# Generated by OpenFakeRAM
VERSION 5.7 ;
BUSBITCHARS "[]" ;
PROPERTYDEFINITIONS
  MACRO width INTEGER ;
  MACRO depth INTEGER ;
  MACRO banks INTEGER ;
END PROPERTYDEFINITIONS
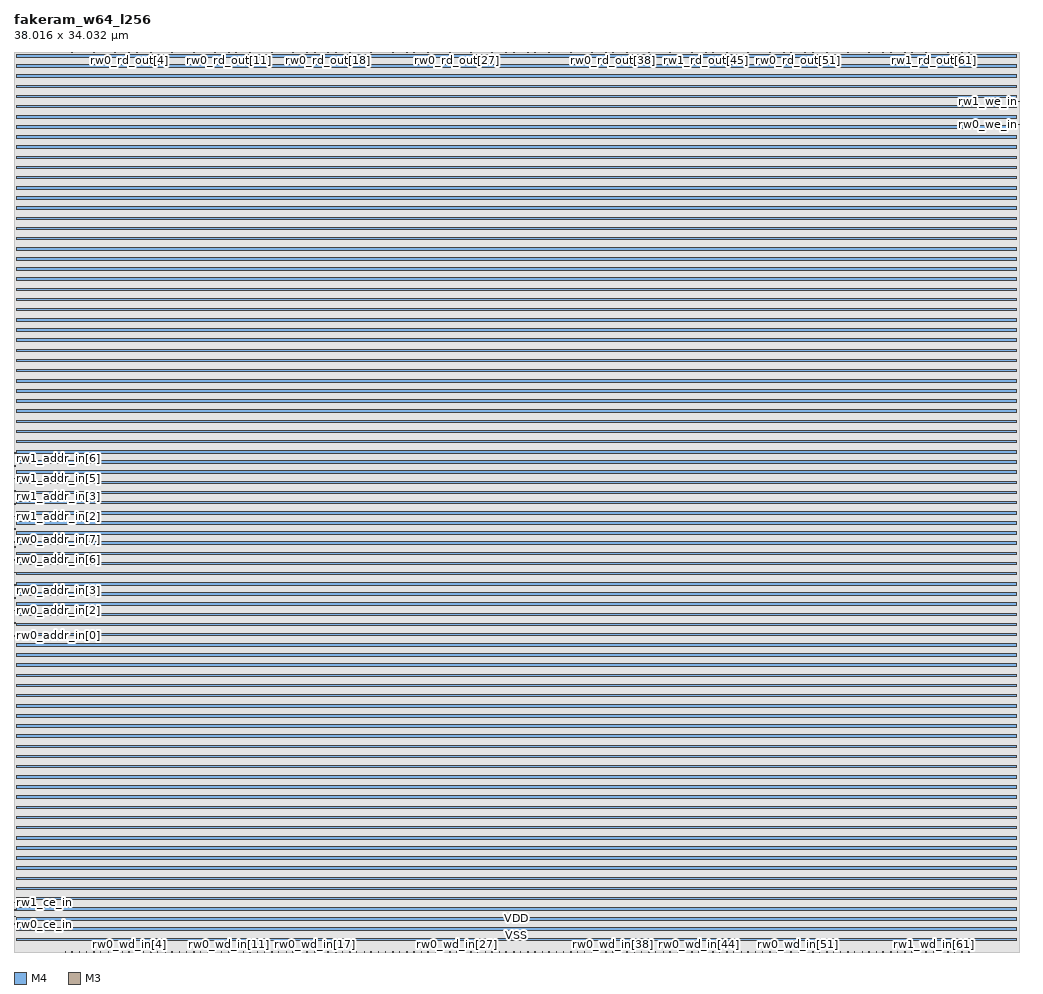
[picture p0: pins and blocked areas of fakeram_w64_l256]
MACRO fakeram_w64_l256
  PROPERTY width 64 ;
  PROPERTY depth 256 ;
  PROPERTY banks 1 ;
  FOREIGN fakeram_w64_l256 0 0 ;
  SYMMETRY X Y R90 ;
  SIZE 38.016 BY 34.032 ;
  CLASS BLOCK ;
  PIN rw0_clk
    DIRECTION INPUT ;
    USE SIGNAL ;
    SHAPE ABUTMENT ;
    PORT
      LAYER M4 ;
      RECT 0.000 1.044 0.048 1.068 ;
    END
  END rw0_clk
  PIN rw0_ce_in
    DIRECTION INPUT ;
    USE SIGNAL ;
    SHAPE ABUTMENT ;
    PORT
      LAYER M4 ;
      RECT 0.000 1.332 0.048 1.356 ;
    END
  END rw0_ce_in
  PIN rw1_clk
    DIRECTION INPUT ;
    USE SIGNAL ;
    SHAPE ABUTMENT ;
    PORT
      LAYER M4 ;
      RECT 0.000 1.572 0.048 1.596 ;
    END
  END rw1_clk
  PIN rw1_ce_in
    DIRECTION INPUT ;
    USE SIGNAL ;
    SHAPE ABUTMENT ;
    PORT
      LAYER M4 ;
      RECT 0.000 1.860 0.048 1.884 ;
    END
  END rw1_ce_in
  PIN rw0_addr_in[0]
    DIRECTION INPUT ;
    USE SIGNAL ;
    SHAPE ABUTMENT ;
    PORT
      LAYER M4 ;
      RECT 0.000 11.940 0.048 11.964 ;
    END
  END rw0_addr_in[0]
  PIN rw0_addr_in[1]
    DIRECTION INPUT ;
    USE SIGNAL ;
    SHAPE ABUTMENT ;
    PORT
      LAYER M4 ;
      RECT 0.000 12.420 0.048 12.444 ;
    END
  END rw0_addr_in[1]
  PIN rw0_addr_in[2]
    DIRECTION INPUT ;
    USE SIGNAL ;
    SHAPE ABUTMENT ;
    PORT
      LAYER M4 ;
      RECT 0.000 12.900 0.048 12.924 ;
    END
  END rw0_addr_in[2]
  PIN rw0_addr_in[3]
    DIRECTION INPUT ;
    USE SIGNAL ;
    SHAPE ABUTMENT ;
    PORT
      LAYER M4 ;
      RECT 0.000 13.380 0.048 13.404 ;
    END
  END rw0_addr_in[3]
  PIN rw0_addr_in[4]
    DIRECTION INPUT ;
    USE SIGNAL ;
    SHAPE ABUTMENT ;
    PORT
      LAYER M4 ;
      RECT 0.000 13.860 0.048 13.884 ;
    END
  END rw0_addr_in[4]
  PIN rw0_addr_in[5]
    DIRECTION INPUT ;
    USE SIGNAL ;
    SHAPE ABUTMENT ;
    PORT
      LAYER M4 ;
      RECT 0.000 14.340 0.048 14.364 ;
    END
  END rw0_addr_in[5]
  PIN rw0_addr_in[6]
    DIRECTION INPUT ;
    USE SIGNAL ;
    SHAPE ABUTMENT ;
    PORT
      LAYER M4 ;
      RECT 0.000 14.820 0.048 14.844 ;
    END
  END rw0_addr_in[6]
  PIN rw0_addr_in[7]
    DIRECTION INPUT ;
    USE SIGNAL ;
    SHAPE ABUTMENT ;
    PORT
      LAYER M4 ;
      RECT 0.000 15.300 0.048 15.324 ;
    END
  END rw0_addr_in[7]
  PIN rw1_addr_in[0]
    DIRECTION INPUT ;
    USE SIGNAL ;
    SHAPE ABUTMENT ;
    PORT
      LAYER M4 ;
      RECT 0.000 15.492 0.048 15.516 ;
    END
  END rw1_addr_in[0]
  PIN rw1_addr_in[1]
    DIRECTION INPUT ;
    USE SIGNAL ;
    SHAPE ABUTMENT ;
    PORT
      LAYER M4 ;
      RECT 0.000 15.972 0.048 15.996 ;
    END
  END rw1_addr_in[1]
  PIN rw1_addr_in[2]
    DIRECTION INPUT ;
    USE SIGNAL ;
    SHAPE ABUTMENT ;
    PORT
      LAYER M4 ;
      RECT 0.000 16.452 0.048 16.476 ;
    END
  END rw1_addr_in[2]
  PIN rw1_addr_in[3]
    DIRECTION INPUT ;
    USE SIGNAL ;
    SHAPE ABUTMENT ;
    PORT
      LAYER M4 ;
      RECT 0.000 16.932 0.048 16.956 ;
    END
  END rw1_addr_in[3]
  PIN rw1_addr_in[4]
    DIRECTION INPUT ;
    USE SIGNAL ;
    SHAPE ABUTMENT ;
    PORT
      LAYER M4 ;
      RECT 0.000 17.412 0.048 17.436 ;
    END
  END rw1_addr_in[4]
  PIN rw1_addr_in[5]
    DIRECTION INPUT ;
    USE SIGNAL ;
    SHAPE ABUTMENT ;
    PORT
      LAYER M4 ;
      RECT 0.000 17.892 0.048 17.916 ;
    END
  END rw1_addr_in[5]
  PIN rw1_addr_in[6]
    DIRECTION INPUT ;
    USE SIGNAL ;
    SHAPE ABUTMENT ;
    PORT
      LAYER M4 ;
      RECT 0.000 18.372 0.048 18.396 ;
    END
  END rw1_addr_in[6]
  PIN rw1_addr_in[7]
    DIRECTION INPUT ;
    USE SIGNAL ;
    SHAPE ABUTMENT ;
    PORT
      LAYER M4 ;
      RECT 0.000 18.852 0.048 18.876 ;
    END
  END rw1_addr_in[7]
  PIN rw1_rd_out[0]
    DIRECTION OUTPUT ;
    USE SIGNAL ;
    SHAPE ABUTMENT ;
    PORT
      LAYER M3 ;
      RECT 1.935 33.996 1.953 34.032 ;
    END
  END rw1_rd_out[0]
  PIN rw0_rd_out[0]
    DIRECTION OUTPUT ;
    USE SIGNAL ;
    SHAPE ABUTMENT ;
    PORT
      LAYER M3 ;
      RECT 2.187 33.996 2.205 34.032 ;
    END
  END rw0_rd_out[0]
  PIN rw1_rd_out[1]
    DIRECTION OUTPUT ;
    USE SIGNAL ;
    SHAPE ABUTMENT ;
    PORT
      LAYER M3 ;
      RECT 2.475 33.996 2.493 34.032 ;
    END
  END rw1_rd_out[1]
  PIN rw0_rd_out[1]
    DIRECTION OUTPUT ;
    USE SIGNAL ;
    SHAPE ABUTMENT ;
    PORT
      LAYER M3 ;
      RECT 2.727 33.996 2.745 34.032 ;
    END
  END rw0_rd_out[1]
  PIN rw1_rd_out[2]
    DIRECTION OUTPUT ;
    USE SIGNAL ;
    SHAPE ABUTMENT ;
    PORT
      LAYER M3 ;
      RECT 3.015 33.996 3.033 34.032 ;
    END
  END rw1_rd_out[2]
  PIN rw0_rd_out[2]
    DIRECTION OUTPUT ;
    USE SIGNAL ;
    SHAPE ABUTMENT ;
    PORT
      LAYER M3 ;
      RECT 3.267 33.996 3.285 34.032 ;
    END
  END rw0_rd_out[2]
  PIN rw1_rd_out[3]
    DIRECTION OUTPUT ;
    USE SIGNAL ;
    SHAPE ABUTMENT ;
    PORT
      LAYER M3 ;
      RECT 3.555 33.996 3.573 34.032 ;
    END
  END rw1_rd_out[3]
  PIN rw0_rd_out[3]
    DIRECTION OUTPUT ;
    USE SIGNAL ;
    SHAPE ABUTMENT ;
    PORT
      LAYER M3 ;
      RECT 3.807 33.996 3.825 34.032 ;
    END
  END rw0_rd_out[3]
  PIN rw1_rd_out[4]
    DIRECTION OUTPUT ;
    USE SIGNAL ;
    SHAPE ABUTMENT ;
    PORT
      LAYER M3 ;
      RECT 4.095 33.996 4.113 34.032 ;
    END
  END rw1_rd_out[4]
  PIN rw0_rd_out[4]
    DIRECTION OUTPUT ;
    USE SIGNAL ;
    SHAPE ABUTMENT ;
    PORT
      LAYER M3 ;
      RECT 4.347 33.996 4.365 34.032 ;
    END
  END rw0_rd_out[4]
  PIN rw1_rd_out[5]
    DIRECTION OUTPUT ;
    USE SIGNAL ;
    SHAPE ABUTMENT ;
    PORT
      LAYER M3 ;
      RECT 4.635 33.996 4.653 34.032 ;
    END
  END rw1_rd_out[5]
  PIN rw0_rd_out[5]
    DIRECTION OUTPUT ;
    USE SIGNAL ;
    SHAPE ABUTMENT ;
    PORT
      LAYER M3 ;
      RECT 4.887 33.996 4.905 34.032 ;
    END
  END rw0_rd_out[5]
  PIN rw1_rd_out[6]
    DIRECTION OUTPUT ;
    USE SIGNAL ;
    SHAPE ABUTMENT ;
    PORT
      LAYER M3 ;
      RECT 5.175 33.996 5.193 34.032 ;
    END
  END rw1_rd_out[6]
  PIN rw0_rd_out[6]
    DIRECTION OUTPUT ;
    USE SIGNAL ;
    SHAPE ABUTMENT ;
    PORT
      LAYER M3 ;
      RECT 5.427 33.996 5.445 34.032 ;
    END
  END rw0_rd_out[6]
  PIN rw1_rd_out[7]
    DIRECTION OUTPUT ;
    USE SIGNAL ;
    SHAPE ABUTMENT ;
    PORT
      LAYER M3 ;
      RECT 5.715 33.996 5.733 34.032 ;
    END
  END rw1_rd_out[7]
  PIN rw0_rd_out[7]
    DIRECTION OUTPUT ;
    USE SIGNAL ;
    SHAPE ABUTMENT ;
    PORT
      LAYER M3 ;
      RECT 5.967 33.996 5.985 34.032 ;
    END
  END rw0_rd_out[7]
  PIN rw1_rd_out[8]
    DIRECTION OUTPUT ;
    USE SIGNAL ;
    SHAPE ABUTMENT ;
    PORT
      LAYER M3 ;
      RECT 6.255 33.996 6.273 34.032 ;
    END
  END rw1_rd_out[8]
  PIN rw0_rd_out[8]
    DIRECTION OUTPUT ;
    USE SIGNAL ;
    SHAPE ABUTMENT ;
    PORT
      LAYER M3 ;
      RECT 6.507 33.996 6.525 34.032 ;
    END
  END rw0_rd_out[8]
  PIN rw1_rd_out[9]
    DIRECTION OUTPUT ;
    USE SIGNAL ;
    SHAPE ABUTMENT ;
    PORT
      LAYER M3 ;
      RECT 6.795 33.996 6.813 34.032 ;
    END
  END rw1_rd_out[9]
  PIN rw0_rd_out[9]
    DIRECTION OUTPUT ;
    USE SIGNAL ;
    SHAPE ABUTMENT ;
    PORT
      LAYER M3 ;
      RECT 7.047 33.996 7.065 34.032 ;
    END
  END rw0_rd_out[9]
  PIN rw1_rd_out[10]
    DIRECTION OUTPUT ;
    USE SIGNAL ;
    SHAPE ABUTMENT ;
    PORT
      LAYER M3 ;
      RECT 7.299 33.996 7.317 34.032 ;
    END
  END rw1_rd_out[10]
  PIN rw0_rd_out[10]
    DIRECTION OUTPUT ;
    USE SIGNAL ;
    SHAPE ABUTMENT ;
    PORT
      LAYER M3 ;
      RECT 7.587 33.996 7.605 34.032 ;
    END
  END rw0_rd_out[10]
  PIN rw1_rd_out[11]
    DIRECTION OUTPUT ;
    USE SIGNAL ;
    SHAPE ABUTMENT ;
    PORT
      LAYER M3 ;
      RECT 7.839 33.996 7.857 34.032 ;
    END
  END rw1_rd_out[11]
  PIN rw0_rd_out[11]
    DIRECTION OUTPUT ;
    USE SIGNAL ;
    SHAPE ABUTMENT ;
    PORT
      LAYER M3 ;
      RECT 8.127 33.996 8.145 34.032 ;
    END
  END rw0_rd_out[11]
  PIN rw1_rd_out[12]
    DIRECTION OUTPUT ;
    USE SIGNAL ;
    SHAPE ABUTMENT ;
    PORT
      LAYER M3 ;
      RECT 8.379 33.996 8.397 34.032 ;
    END
  END rw1_rd_out[12]
  PIN rw0_rd_out[12]
    DIRECTION OUTPUT ;
    USE SIGNAL ;
    SHAPE ABUTMENT ;
    PORT
      LAYER M3 ;
      RECT 8.667 33.996 8.685 34.032 ;
    END
  END rw0_rd_out[12]
  PIN rw1_rd_out[13]
    DIRECTION OUTPUT ;
    USE SIGNAL ;
    SHAPE ABUTMENT ;
    PORT
      LAYER M3 ;
      RECT 8.919 33.996 8.937 34.032 ;
    END
  END rw1_rd_out[13]
  PIN rw0_rd_out[13]
    DIRECTION OUTPUT ;
    USE SIGNAL ;
    SHAPE ABUTMENT ;
    PORT
      LAYER M3 ;
      RECT 9.207 33.996 9.225 34.032 ;
    END
  END rw0_rd_out[13]
  PIN rw1_rd_out[14]
    DIRECTION OUTPUT ;
    USE SIGNAL ;
    SHAPE ABUTMENT ;
    PORT
      LAYER M3 ;
      RECT 9.459 33.996 9.477 34.032 ;
    END
  END rw1_rd_out[14]
  PIN rw0_rd_out[14]
    DIRECTION OUTPUT ;
    USE SIGNAL ;
    SHAPE ABUTMENT ;
    PORT
      LAYER M3 ;
      RECT 9.747 33.996 9.765 34.032 ;
    END
  END rw0_rd_out[14]
  PIN rw1_rd_out[15]
    DIRECTION OUTPUT ;
    USE SIGNAL ;
    SHAPE ABUTMENT ;
    PORT
      LAYER M3 ;
      RECT 9.999 33.996 10.017 34.032 ;
    END
  END rw1_rd_out[15]
  PIN rw0_rd_out[15]
    DIRECTION OUTPUT ;
    USE SIGNAL ;
    SHAPE ABUTMENT ;
    PORT
      LAYER M3 ;
      RECT 10.287 33.996 10.305 34.032 ;
    END
  END rw0_rd_out[15]
  PIN rw1_rd_out[16]
    DIRECTION OUTPUT ;
    USE SIGNAL ;
    SHAPE ABUTMENT ;
    PORT
      LAYER M3 ;
      RECT 10.539 33.996 10.557 34.032 ;
    END
  END rw1_rd_out[16]
  PIN rw0_rd_out[16]
    DIRECTION OUTPUT ;
    USE SIGNAL ;
    SHAPE ABUTMENT ;
    PORT
      LAYER M3 ;
      RECT 10.827 33.996 10.845 34.032 ;
    END
  END rw0_rd_out[16]
  PIN rw1_rd_out[17]
    DIRECTION OUTPUT ;
    USE SIGNAL ;
    SHAPE ABUTMENT ;
    PORT
      LAYER M3 ;
      RECT 11.079 33.996 11.097 34.032 ;
    END
  END rw1_rd_out[17]
  PIN rw0_rd_out[17]
    DIRECTION OUTPUT ;
    USE SIGNAL ;
    SHAPE ABUTMENT ;
    PORT
      LAYER M3 ;
      RECT 11.367 33.996 11.385 34.032 ;
    END
  END rw0_rd_out[17]
  PIN rw1_rd_out[18]
    DIRECTION OUTPUT ;
    USE SIGNAL ;
    SHAPE ABUTMENT ;
    PORT
      LAYER M3 ;
      RECT 11.619 33.996 11.637 34.032 ;
    END
  END rw1_rd_out[18]
  PIN rw0_rd_out[18]
    DIRECTION OUTPUT ;
    USE SIGNAL ;
    SHAPE ABUTMENT ;
    PORT
      LAYER M3 ;
      RECT 11.871 33.996 11.889 34.032 ;
    END
  END rw0_rd_out[18]
  PIN rw1_rd_out[19]
    DIRECTION OUTPUT ;
    USE SIGNAL ;
    SHAPE ABUTMENT ;
    PORT
      LAYER M3 ;
      RECT 12.159 33.996 12.177 34.032 ;
    END
  END rw1_rd_out[19]
  PIN rw0_rd_out[19]
    DIRECTION OUTPUT ;
    USE SIGNAL ;
    SHAPE ABUTMENT ;
    PORT
      LAYER M3 ;
      RECT 12.411 33.996 12.429 34.032 ;
    END
  END rw0_rd_out[19]
  PIN rw1_rd_out[20]
    DIRECTION OUTPUT ;
    USE SIGNAL ;
    SHAPE ABUTMENT ;
    PORT
      LAYER M3 ;
      RECT 12.699 33.996 12.717 34.032 ;
    END
  END rw1_rd_out[20]
  PIN rw0_rd_out[20]
    DIRECTION OUTPUT ;
    USE SIGNAL ;
    SHAPE ABUTMENT ;
    PORT
      LAYER M3 ;
      RECT 12.951 33.996 12.969 34.032 ;
    END
  END rw0_rd_out[20]
  PIN rw1_rd_out[21]
    DIRECTION OUTPUT ;
    USE SIGNAL ;
    SHAPE ABUTMENT ;
    PORT
      LAYER M3 ;
      RECT 13.239 33.996 13.257 34.032 ;
    END
  END rw1_rd_out[21]
  PIN rw0_rd_out[21]
    DIRECTION OUTPUT ;
    USE SIGNAL ;
    SHAPE ABUTMENT ;
    PORT
      LAYER M3 ;
      RECT 13.491 33.996 13.509 34.032 ;
    END
  END rw0_rd_out[21]
  PIN rw1_rd_out[22]
    DIRECTION OUTPUT ;
    USE SIGNAL ;
    SHAPE ABUTMENT ;
    PORT
      LAYER M3 ;
      RECT 13.779 33.996 13.797 34.032 ;
    END
  END rw1_rd_out[22]
  PIN rw0_rd_out[22]
    DIRECTION OUTPUT ;
    USE SIGNAL ;
    SHAPE ABUTMENT ;
    PORT
      LAYER M3 ;
      RECT 14.031 33.996 14.049 34.032 ;
    END
  END rw0_rd_out[22]
  PIN rw1_rd_out[23]
    DIRECTION OUTPUT ;
    USE SIGNAL ;
    SHAPE ABUTMENT ;
    PORT
      LAYER M3 ;
      RECT 14.319 33.996 14.337 34.032 ;
    END
  END rw1_rd_out[23]
  PIN rw0_rd_out[23]
    DIRECTION OUTPUT ;
    USE SIGNAL ;
    SHAPE ABUTMENT ;
    PORT
      LAYER M3 ;
      RECT 14.571 33.996 14.589 34.032 ;
    END
  END rw0_rd_out[23]
  PIN rw1_rd_out[24]
    DIRECTION OUTPUT ;
    USE SIGNAL ;
    SHAPE ABUTMENT ;
    PORT
      LAYER M3 ;
      RECT 14.859 33.996 14.877 34.032 ;
    END
  END rw1_rd_out[24]
  PIN rw0_rd_out[24]
    DIRECTION OUTPUT ;
    USE SIGNAL ;
    SHAPE ABUTMENT ;
    PORT
      LAYER M3 ;
      RECT 15.111 33.996 15.129 34.032 ;
    END
  END rw0_rd_out[24]
  PIN rw1_rd_out[25]
    DIRECTION OUTPUT ;
    USE SIGNAL ;
    SHAPE ABUTMENT ;
    PORT
      LAYER M3 ;
      RECT 15.399 33.996 15.417 34.032 ;
    END
  END rw1_rd_out[25]
  PIN rw0_rd_out[25]
    DIRECTION OUTPUT ;
    USE SIGNAL ;
    SHAPE ABUTMENT ;
    PORT
      LAYER M3 ;
      RECT 15.651 33.996 15.669 34.032 ;
    END
  END rw0_rd_out[25]
  PIN rw1_rd_out[26]
    DIRECTION OUTPUT ;
    USE SIGNAL ;
    SHAPE ABUTMENT ;
    PORT
      LAYER M3 ;
      RECT 15.939 33.996 15.957 34.032 ;
    END
  END rw1_rd_out[26]
  PIN rw0_rd_out[26]
    DIRECTION OUTPUT ;
    USE SIGNAL ;
    SHAPE ABUTMENT ;
    PORT
      LAYER M3 ;
      RECT 16.191 33.996 16.209 34.032 ;
    END
  END rw0_rd_out[26]
  PIN rw1_rd_out[27]
    DIRECTION OUTPUT ;
    USE SIGNAL ;
    SHAPE ABUTMENT ;
    PORT
      LAYER M3 ;
      RECT 16.479 33.996 16.497 34.032 ;
    END
  END rw1_rd_out[27]
  PIN rw0_rd_out[27]
    DIRECTION OUTPUT ;
    USE SIGNAL ;
    SHAPE ABUTMENT ;
    PORT
      LAYER M3 ;
      RECT 16.731 33.996 16.749 34.032 ;
    END
  END rw0_rd_out[27]
  PIN rw1_rd_out[28]
    DIRECTION OUTPUT ;
    USE SIGNAL ;
    SHAPE ABUTMENT ;
    PORT
      LAYER M3 ;
      RECT 16.983 33.996 17.001 34.032 ;
    END
  END rw1_rd_out[28]
  PIN rw0_rd_out[28]
    DIRECTION OUTPUT ;
    USE SIGNAL ;
    SHAPE ABUTMENT ;
    PORT
      LAYER M3 ;
      RECT 17.271 33.996 17.289 34.032 ;
    END
  END rw0_rd_out[28]
  PIN rw1_rd_out[29]
    DIRECTION OUTPUT ;
    USE SIGNAL ;
    SHAPE ABUTMENT ;
    PORT
      LAYER M3 ;
      RECT 17.523 33.996 17.541 34.032 ;
    END
  END rw1_rd_out[29]
  PIN rw0_rd_out[29]
    DIRECTION OUTPUT ;
    USE SIGNAL ;
    SHAPE ABUTMENT ;
    PORT
      LAYER M3 ;
      RECT 17.811 33.996 17.829 34.032 ;
    END
  END rw0_rd_out[29]
  PIN rw1_rd_out[30]
    DIRECTION OUTPUT ;
    USE SIGNAL ;
    SHAPE ABUTMENT ;
    PORT
      LAYER M3 ;
      RECT 18.063 33.996 18.081 34.032 ;
    END
  END rw1_rd_out[30]
  PIN rw0_rd_out[30]
    DIRECTION OUTPUT ;
    USE SIGNAL ;
    SHAPE ABUTMENT ;
    PORT
      LAYER M3 ;
      RECT 18.351 33.996 18.369 34.032 ;
    END
  END rw0_rd_out[30]
  PIN rw1_rd_out[31]
    DIRECTION OUTPUT ;
    USE SIGNAL ;
    SHAPE ABUTMENT ;
    PORT
      LAYER M3 ;
      RECT 18.603 33.996 18.621 34.032 ;
    END
  END rw1_rd_out[31]
  PIN rw0_rd_out[31]
    DIRECTION OUTPUT ;
    USE SIGNAL ;
    SHAPE ABUTMENT ;
    PORT
      LAYER M3 ;
      RECT 18.891 33.996 18.909 34.032 ;
    END
  END rw0_rd_out[31]
  PIN rw1_rd_out[32]
    DIRECTION OUTPUT ;
    USE SIGNAL ;
    SHAPE ABUTMENT ;
    PORT
      LAYER M3 ;
      RECT 19.143 33.996 19.161 34.032 ;
    END
  END rw1_rd_out[32]
  PIN rw0_rd_out[32]
    DIRECTION OUTPUT ;
    USE SIGNAL ;
    SHAPE ABUTMENT ;
    PORT
      LAYER M3 ;
      RECT 19.431 33.996 19.449 34.032 ;
    END
  END rw0_rd_out[32]
  PIN rw1_rd_out[33]
    DIRECTION OUTPUT ;
    USE SIGNAL ;
    SHAPE ABUTMENT ;
    PORT
      LAYER M3 ;
      RECT 19.683 33.996 19.701 34.032 ;
    END
  END rw1_rd_out[33]
  PIN rw0_rd_out[33]
    DIRECTION OUTPUT ;
    USE SIGNAL ;
    SHAPE ABUTMENT ;
    PORT
      LAYER M3 ;
      RECT 19.971 33.996 19.989 34.032 ;
    END
  END rw0_rd_out[33]
  PIN rw1_rd_out[34]
    DIRECTION OUTPUT ;
    USE SIGNAL ;
    SHAPE ABUTMENT ;
    PORT
      LAYER M3 ;
      RECT 20.223 33.996 20.241 34.032 ;
    END
  END rw1_rd_out[34]
  PIN rw0_rd_out[34]
    DIRECTION OUTPUT ;
    USE SIGNAL ;
    SHAPE ABUTMENT ;
    PORT
      LAYER M3 ;
      RECT 20.511 33.996 20.529 34.032 ;
    END
  END rw0_rd_out[34]
  PIN rw1_rd_out[35]
    DIRECTION OUTPUT ;
    USE SIGNAL ;
    SHAPE ABUTMENT ;
    PORT
      LAYER M3 ;
      RECT 20.763 33.996 20.781 34.032 ;
    END
  END rw1_rd_out[35]
  PIN rw0_rd_out[35]
    DIRECTION OUTPUT ;
    USE SIGNAL ;
    SHAPE ABUTMENT ;
    PORT
      LAYER M3 ;
      RECT 21.051 33.996 21.069 34.032 ;
    END
  END rw0_rd_out[35]
  PIN rw1_rd_out[36]
    DIRECTION OUTPUT ;
    USE SIGNAL ;
    SHAPE ABUTMENT ;
    PORT
      LAYER M3 ;
      RECT 21.303 33.996 21.321 34.032 ;
    END
  END rw1_rd_out[36]
  PIN rw0_rd_out[36]
    DIRECTION OUTPUT ;
    USE SIGNAL ;
    SHAPE ABUTMENT ;
    PORT
      LAYER M3 ;
      RECT 21.555 33.996 21.573 34.032 ;
    END
  END rw0_rd_out[36]
  PIN rw1_rd_out[37]
    DIRECTION OUTPUT ;
    USE SIGNAL ;
    SHAPE ABUTMENT ;
    PORT
      LAYER M3 ;
      RECT 21.843 33.996 21.861 34.032 ;
    END
  END rw1_rd_out[37]
  PIN rw0_rd_out[37]
    DIRECTION OUTPUT ;
    USE SIGNAL ;
    SHAPE ABUTMENT ;
    PORT
      LAYER M3 ;
      RECT 22.095 33.996 22.113 34.032 ;
    END
  END rw0_rd_out[37]
  PIN rw1_rd_out[38]
    DIRECTION OUTPUT ;
    USE SIGNAL ;
    SHAPE ABUTMENT ;
    PORT
      LAYER M3 ;
      RECT 22.383 33.996 22.401 34.032 ;
    END
  END rw1_rd_out[38]
  PIN rw0_rd_out[38]
    DIRECTION OUTPUT ;
    USE SIGNAL ;
    SHAPE ABUTMENT ;
    PORT
      LAYER M3 ;
      RECT 22.635 33.996 22.653 34.032 ;
    END
  END rw0_rd_out[38]
  PIN rw1_rd_out[39]
    DIRECTION OUTPUT ;
    USE SIGNAL ;
    SHAPE ABUTMENT ;
    PORT
      LAYER M3 ;
      RECT 22.923 33.996 22.941 34.032 ;
    END
  END rw1_rd_out[39]
  PIN rw0_rd_out[39]
    DIRECTION OUTPUT ;
    USE SIGNAL ;
    SHAPE ABUTMENT ;
    PORT
      LAYER M3 ;
      RECT 23.175 33.996 23.193 34.032 ;
    END
  END rw0_rd_out[39]
  PIN rw1_rd_out[40]
    DIRECTION OUTPUT ;
    USE SIGNAL ;
    SHAPE ABUTMENT ;
    PORT
      LAYER M3 ;
      RECT 23.463 33.996 23.481 34.032 ;
    END
  END rw1_rd_out[40]
  PIN rw0_rd_out[40]
    DIRECTION OUTPUT ;
    USE SIGNAL ;
    SHAPE ABUTMENT ;
    PORT
      LAYER M3 ;
      RECT 23.715 33.996 23.733 34.032 ;
    END
  END rw0_rd_out[40]
  PIN rw1_rd_out[41]
    DIRECTION OUTPUT ;
    USE SIGNAL ;
    SHAPE ABUTMENT ;
    PORT
      LAYER M3 ;
      RECT 24.003 33.996 24.021 34.032 ;
    END
  END rw1_rd_out[41]
  PIN rw0_rd_out[41]
    DIRECTION OUTPUT ;
    USE SIGNAL ;
    SHAPE ABUTMENT ;
    PORT
      LAYER M3 ;
      RECT 24.255 33.996 24.273 34.032 ;
    END
  END rw0_rd_out[41]
  PIN rw1_rd_out[42]
    DIRECTION OUTPUT ;
    USE SIGNAL ;
    SHAPE ABUTMENT ;
    PORT
      LAYER M3 ;
      RECT 24.543 33.996 24.561 34.032 ;
    END
  END rw1_rd_out[42]
  PIN rw0_rd_out[42]
    DIRECTION OUTPUT ;
    USE SIGNAL ;
    SHAPE ABUTMENT ;
    PORT
      LAYER M3 ;
      RECT 24.795 33.996 24.813 34.032 ;
    END
  END rw0_rd_out[42]
  PIN rw1_rd_out[43]
    DIRECTION OUTPUT ;
    USE SIGNAL ;
    SHAPE ABUTMENT ;
    PORT
      LAYER M3 ;
      RECT 25.083 33.996 25.101 34.032 ;
    END
  END rw1_rd_out[43]
  PIN rw0_rd_out[43]
    DIRECTION OUTPUT ;
    USE SIGNAL ;
    SHAPE ABUTMENT ;
    PORT
      LAYER M3 ;
      RECT 25.335 33.996 25.353 34.032 ;
    END
  END rw0_rd_out[43]
  PIN rw1_rd_out[44]
    DIRECTION OUTPUT ;
    USE SIGNAL ;
    SHAPE ABUTMENT ;
    PORT
      LAYER M3 ;
      RECT 25.623 33.996 25.641 34.032 ;
    END
  END rw1_rd_out[44]
  PIN rw0_rd_out[44]
    DIRECTION OUTPUT ;
    USE SIGNAL ;
    SHAPE ABUTMENT ;
    PORT
      LAYER M3 ;
      RECT 25.875 33.996 25.893 34.032 ;
    END
  END rw0_rd_out[44]
  PIN rw1_rd_out[45]
    DIRECTION OUTPUT ;
    USE SIGNAL ;
    SHAPE ABUTMENT ;
    PORT
      LAYER M3 ;
      RECT 26.163 33.996 26.181 34.032 ;
    END
  END rw1_rd_out[45]
  PIN rw0_rd_out[45]
    DIRECTION OUTPUT ;
    USE SIGNAL ;
    SHAPE ABUTMENT ;
    PORT
      LAYER M3 ;
      RECT 26.415 33.996 26.433 34.032 ;
    END
  END rw0_rd_out[45]
  PIN rw1_rd_out[46]
    DIRECTION OUTPUT ;
    USE SIGNAL ;
    SHAPE ABUTMENT ;
    PORT
      LAYER M3 ;
      RECT 26.667 33.996 26.685 34.032 ;
    END
  END rw1_rd_out[46]
  PIN rw0_rd_out[46]
    DIRECTION OUTPUT ;
    USE SIGNAL ;
    SHAPE ABUTMENT ;
    PORT
      LAYER M3 ;
      RECT 26.955 33.996 26.973 34.032 ;
    END
  END rw0_rd_out[46]
  PIN rw1_rd_out[47]
    DIRECTION OUTPUT ;
    USE SIGNAL ;
    SHAPE ABUTMENT ;
    PORT
      LAYER M3 ;
      RECT 27.207 33.996 27.225 34.032 ;
    END
  END rw1_rd_out[47]
  PIN rw0_rd_out[47]
    DIRECTION OUTPUT ;
    USE SIGNAL ;
    SHAPE ABUTMENT ;
    PORT
      LAYER M3 ;
      RECT 27.495 33.996 27.513 34.032 ;
    END
  END rw0_rd_out[47]
  PIN rw1_rd_out[48]
    DIRECTION OUTPUT ;
    USE SIGNAL ;
    SHAPE ABUTMENT ;
    PORT
      LAYER M3 ;
      RECT 27.747 33.996 27.765 34.032 ;
    END
  END rw1_rd_out[48]
  PIN rw0_rd_out[48]
    DIRECTION OUTPUT ;
    USE SIGNAL ;
    SHAPE ABUTMENT ;
    PORT
      LAYER M3 ;
      RECT 28.035 33.996 28.053 34.032 ;
    END
  END rw0_rd_out[48]
  PIN rw1_rd_out[49]
    DIRECTION OUTPUT ;
    USE SIGNAL ;
    SHAPE ABUTMENT ;
    PORT
      LAYER M3 ;
      RECT 28.287 33.996 28.305 34.032 ;
    END
  END rw1_rd_out[49]
  PIN rw0_rd_out[49]
    DIRECTION OUTPUT ;
    USE SIGNAL ;
    SHAPE ABUTMENT ;
    PORT
      LAYER M3 ;
      RECT 28.575 33.996 28.593 34.032 ;
    END
  END rw0_rd_out[49]
  PIN rw1_rd_out[50]
    DIRECTION OUTPUT ;
    USE SIGNAL ;
    SHAPE ABUTMENT ;
    PORT
      LAYER M3 ;
      RECT 28.827 33.996 28.845 34.032 ;
    END
  END rw1_rd_out[50]
  PIN rw0_rd_out[50]
    DIRECTION OUTPUT ;
    USE SIGNAL ;
    SHAPE ABUTMENT ;
    PORT
      LAYER M3 ;
      RECT 29.115 33.996 29.133 34.032 ;
    END
  END rw0_rd_out[50]
  PIN rw1_rd_out[51]
    DIRECTION OUTPUT ;
    USE SIGNAL ;
    SHAPE ABUTMENT ;
    PORT
      LAYER M3 ;
      RECT 29.367 33.996 29.385 34.032 ;
    END
  END rw1_rd_out[51]
  PIN rw0_rd_out[51]
    DIRECTION OUTPUT ;
    USE SIGNAL ;
    SHAPE ABUTMENT ;
    PORT
      LAYER M3 ;
      RECT 29.655 33.996 29.673 34.032 ;
    END
  END rw0_rd_out[51]
  PIN rw1_rd_out[52]
    DIRECTION OUTPUT ;
    USE SIGNAL ;
    SHAPE ABUTMENT ;
    PORT
      LAYER M3 ;
      RECT 29.907 33.996 29.925 34.032 ;
    END
  END rw1_rd_out[52]
  PIN rw0_rd_out[52]
    DIRECTION OUTPUT ;
    USE SIGNAL ;
    SHAPE ABUTMENT ;
    PORT
      LAYER M3 ;
      RECT 30.195 33.996 30.213 34.032 ;
    END
  END rw0_rd_out[52]
  PIN rw1_rd_out[53]
    DIRECTION OUTPUT ;
    USE SIGNAL ;
    SHAPE ABUTMENT ;
    PORT
      LAYER M3 ;
      RECT 30.447 33.996 30.465 34.032 ;
    END
  END rw1_rd_out[53]
  PIN rw0_rd_out[53]
    DIRECTION OUTPUT ;
    USE SIGNAL ;
    SHAPE ABUTMENT ;
    PORT
      LAYER M3 ;
      RECT 30.735 33.996 30.753 34.032 ;
    END
  END rw0_rd_out[53]
  PIN rw1_rd_out[54]
    DIRECTION OUTPUT ;
    USE SIGNAL ;
    SHAPE ABUTMENT ;
    PORT
      LAYER M3 ;
      RECT 30.987 33.996 31.005 34.032 ;
    END
  END rw1_rd_out[54]
  PIN rw0_rd_out[54]
    DIRECTION OUTPUT ;
    USE SIGNAL ;
    SHAPE ABUTMENT ;
    PORT
      LAYER M3 ;
      RECT 31.239 33.996 31.257 34.032 ;
    END
  END rw0_rd_out[54]
  PIN rw1_rd_out[55]
    DIRECTION OUTPUT ;
    USE SIGNAL ;
    SHAPE ABUTMENT ;
    PORT
      LAYER M3 ;
      RECT 31.527 33.996 31.545 34.032 ;
    END
  END rw1_rd_out[55]
  PIN rw0_rd_out[55]
    DIRECTION OUTPUT ;
    USE SIGNAL ;
    SHAPE ABUTMENT ;
    PORT
      LAYER M3 ;
      RECT 31.779 33.996 31.797 34.032 ;
    END
  END rw0_rd_out[55]
  PIN rw1_rd_out[56]
    DIRECTION OUTPUT ;
    USE SIGNAL ;
    SHAPE ABUTMENT ;
    PORT
      LAYER M3 ;
      RECT 32.067 33.996 32.085 34.032 ;
    END
  END rw1_rd_out[56]
  PIN rw0_rd_out[56]
    DIRECTION OUTPUT ;
    USE SIGNAL ;
    SHAPE ABUTMENT ;
    PORT
      LAYER M3 ;
      RECT 32.319 33.996 32.337 34.032 ;
    END
  END rw0_rd_out[56]
  PIN rw1_rd_out[57]
    DIRECTION OUTPUT ;
    USE SIGNAL ;
    SHAPE ABUTMENT ;
    PORT
      LAYER M3 ;
      RECT 32.607 33.996 32.625 34.032 ;
    END
  END rw1_rd_out[57]
  PIN rw0_rd_out[57]
    DIRECTION OUTPUT ;
    USE SIGNAL ;
    SHAPE ABUTMENT ;
    PORT
      LAYER M3 ;
      RECT 32.859 33.996 32.877 34.032 ;
    END
  END rw0_rd_out[57]
  PIN rw1_rd_out[58]
    DIRECTION OUTPUT ;
    USE SIGNAL ;
    SHAPE ABUTMENT ;
    PORT
      LAYER M3 ;
      RECT 33.147 33.996 33.165 34.032 ;
    END
  END rw1_rd_out[58]
  PIN rw0_rd_out[58]
    DIRECTION OUTPUT ;
    USE SIGNAL ;
    SHAPE ABUTMENT ;
    PORT
      LAYER M3 ;
      RECT 33.399 33.996 33.417 34.032 ;
    END
  END rw0_rd_out[58]
  PIN rw1_rd_out[59]
    DIRECTION OUTPUT ;
    USE SIGNAL ;
    SHAPE ABUTMENT ;
    PORT
      LAYER M3 ;
      RECT 33.687 33.996 33.705 34.032 ;
    END
  END rw1_rd_out[59]
  PIN rw0_rd_out[59]
    DIRECTION OUTPUT ;
    USE SIGNAL ;
    SHAPE ABUTMENT ;
    PORT
      LAYER M3 ;
      RECT 33.939 33.996 33.957 34.032 ;
    END
  END rw0_rd_out[59]
  PIN rw1_rd_out[60]
    DIRECTION OUTPUT ;
    USE SIGNAL ;
    SHAPE ABUTMENT ;
    PORT
      LAYER M3 ;
      RECT 34.227 33.996 34.245 34.032 ;
    END
  END rw1_rd_out[60]
  PIN rw0_rd_out[60]
    DIRECTION OUTPUT ;
    USE SIGNAL ;
    SHAPE ABUTMENT ;
    PORT
      LAYER M3 ;
      RECT 34.479 33.996 34.497 34.032 ;
    END
  END rw0_rd_out[60]
  PIN rw1_rd_out[61]
    DIRECTION OUTPUT ;
    USE SIGNAL ;
    SHAPE ABUTMENT ;
    PORT
      LAYER M3 ;
      RECT 34.767 33.996 34.785 34.032 ;
    END
  END rw1_rd_out[61]
  PIN rw0_rd_out[61]
    DIRECTION OUTPUT ;
    USE SIGNAL ;
    SHAPE ABUTMENT ;
    PORT
      LAYER M3 ;
      RECT 35.019 33.996 35.037 34.032 ;
    END
  END rw0_rd_out[61]
  PIN rw1_rd_out[62]
    DIRECTION OUTPUT ;
    USE SIGNAL ;
    SHAPE ABUTMENT ;
    PORT
      LAYER M3 ;
      RECT 35.307 33.996 35.325 34.032 ;
    END
  END rw1_rd_out[62]
  PIN rw0_rd_out[62]
    DIRECTION OUTPUT ;
    USE SIGNAL ;
    SHAPE ABUTMENT ;
    PORT
      LAYER M3 ;
      RECT 35.559 33.996 35.577 34.032 ;
    END
  END rw0_rd_out[62]
  PIN rw1_rd_out[63]
    DIRECTION OUTPUT ;
    USE SIGNAL ;
    SHAPE ABUTMENT ;
    PORT
      LAYER M3 ;
      RECT 35.847 33.996 35.865 34.032 ;
    END
  END rw1_rd_out[63]
  PIN rw0_rd_out[63]
    DIRECTION OUTPUT ;
    USE SIGNAL ;
    SHAPE ABUTMENT ;
    PORT
      LAYER M3 ;
      RECT 36.099 33.996 36.117 34.032 ;
    END
  END rw0_rd_out[63]
  PIN rw0_we_in
    DIRECTION INPUT ;
    USE SIGNAL ;
    SHAPE ABUTMENT ;
    PORT
      LAYER M4 ;
      RECT 37.968 31.284 38.016 31.308 ;
    END
  END rw0_we_in
  PIN rw1_we_in
    DIRECTION INPUT ;
    USE SIGNAL ;
    SHAPE ABUTMENT ;
    PORT
      LAYER M4 ;
      RECT 37.968 32.148 38.016 32.172 ;
    END
  END rw1_we_in
  PIN rw1_wd_in[0]
    DIRECTION INPUT ;
    USE SIGNAL ;
    SHAPE ABUTMENT ;
    PORT
      LAYER M3 ;
      RECT 1.935 0.000 1.953 0.036 ;
    END
  END rw1_wd_in[0]
  PIN rw0_wd_in[0]
    DIRECTION INPUT ;
    USE SIGNAL ;
    SHAPE ABUTMENT ;
    PORT
      LAYER M3 ;
      RECT 2.187 0.000 2.205 0.036 ;
    END
  END rw0_wd_in[0]
  PIN rw1_wd_in[1]
    DIRECTION INPUT ;
    USE SIGNAL ;
    SHAPE ABUTMENT ;
    PORT
      LAYER M3 ;
      RECT 2.475 0.000 2.493 0.036 ;
    END
  END rw1_wd_in[1]
  PIN rw0_wd_in[1]
    DIRECTION INPUT ;
    USE SIGNAL ;
    SHAPE ABUTMENT ;
    PORT
      LAYER M3 ;
      RECT 2.727 0.000 2.745 0.036 ;
    END
  END rw0_wd_in[1]
  PIN rw1_wd_in[2]
    DIRECTION INPUT ;
    USE SIGNAL ;
    SHAPE ABUTMENT ;
    PORT
      LAYER M3 ;
      RECT 3.015 0.000 3.033 0.036 ;
    END
  END rw1_wd_in[2]
  PIN rw0_wd_in[2]
    DIRECTION INPUT ;
    USE SIGNAL ;
    SHAPE ABUTMENT ;
    PORT
      LAYER M3 ;
      RECT 3.267 0.000 3.285 0.036 ;
    END
  END rw0_wd_in[2]
  PIN rw1_wd_in[3]
    DIRECTION INPUT ;
    USE SIGNAL ;
    SHAPE ABUTMENT ;
    PORT
      LAYER M3 ;
      RECT 3.555 0.000 3.573 0.036 ;
    END
  END rw1_wd_in[3]
  PIN rw0_wd_in[3]
    DIRECTION INPUT ;
    USE SIGNAL ;
    SHAPE ABUTMENT ;
    PORT
      LAYER M3 ;
      RECT 3.807 0.000 3.825 0.036 ;
    END
  END rw0_wd_in[3]
  PIN rw1_wd_in[4]
    DIRECTION INPUT ;
    USE SIGNAL ;
    SHAPE ABUTMENT ;
    PORT
      LAYER M3 ;
      RECT 4.095 0.000 4.113 0.036 ;
    END
  END rw1_wd_in[4]
  PIN rw0_wd_in[4]
    DIRECTION INPUT ;
    USE SIGNAL ;
    SHAPE ABUTMENT ;
    PORT
      LAYER M3 ;
      RECT 4.347 0.000 4.365 0.036 ;
    END
  END rw0_wd_in[4]
  PIN rw1_wd_in[5]
    DIRECTION INPUT ;
    USE SIGNAL ;
    SHAPE ABUTMENT ;
    PORT
      LAYER M3 ;
      RECT 4.635 0.000 4.653 0.036 ;
    END
  END rw1_wd_in[5]
  PIN rw0_wd_in[5]
    DIRECTION INPUT ;
    USE SIGNAL ;
    SHAPE ABUTMENT ;
    PORT
      LAYER M3 ;
      RECT 4.887 0.000 4.905 0.036 ;
    END
  END rw0_wd_in[5]
  PIN rw1_wd_in[6]
    DIRECTION INPUT ;
    USE SIGNAL ;
    SHAPE ABUTMENT ;
    PORT
      LAYER M3 ;
      RECT 5.175 0.000 5.193 0.036 ;
    END
  END rw1_wd_in[6]
  PIN rw0_wd_in[6]
    DIRECTION INPUT ;
    USE SIGNAL ;
    SHAPE ABUTMENT ;
    PORT
      LAYER M3 ;
      RECT 5.427 0.000 5.445 0.036 ;
    END
  END rw0_wd_in[6]
  PIN rw1_wd_in[7]
    DIRECTION INPUT ;
    USE SIGNAL ;
    SHAPE ABUTMENT ;
    PORT
      LAYER M3 ;
      RECT 5.715 0.000 5.733 0.036 ;
    END
  END rw1_wd_in[7]
  PIN rw0_wd_in[7]
    DIRECTION INPUT ;
    USE SIGNAL ;
    SHAPE ABUTMENT ;
    PORT
      LAYER M3 ;
      RECT 5.967 0.000 5.985 0.036 ;
    END
  END rw0_wd_in[7]
  PIN rw1_wd_in[8]
    DIRECTION INPUT ;
    USE SIGNAL ;
    SHAPE ABUTMENT ;
    PORT
      LAYER M3 ;
      RECT 6.255 0.000 6.273 0.036 ;
    END
  END rw1_wd_in[8]
  PIN rw0_wd_in[8]
    DIRECTION INPUT ;
    USE SIGNAL ;
    SHAPE ABUTMENT ;
    PORT
      LAYER M3 ;
      RECT 6.507 0.000 6.525 0.036 ;
    END
  END rw0_wd_in[8]
  PIN rw1_wd_in[9]
    DIRECTION INPUT ;
    USE SIGNAL ;
    SHAPE ABUTMENT ;
    PORT
      LAYER M3 ;
      RECT 6.795 0.000 6.813 0.036 ;
    END
  END rw1_wd_in[9]
  PIN rw0_wd_in[9]
    DIRECTION INPUT ;
    USE SIGNAL ;
    SHAPE ABUTMENT ;
    PORT
      LAYER M3 ;
      RECT 7.047 0.000 7.065 0.036 ;
    END
  END rw0_wd_in[9]
  PIN rw1_wd_in[10]
    DIRECTION INPUT ;
    USE SIGNAL ;
    SHAPE ABUTMENT ;
    PORT
      LAYER M3 ;
      RECT 7.299 0.000 7.317 0.036 ;
    END
  END rw1_wd_in[10]
  PIN rw0_wd_in[10]
    DIRECTION INPUT ;
    USE SIGNAL ;
    SHAPE ABUTMENT ;
    PORT
      LAYER M3 ;
      RECT 7.587 0.000 7.605 0.036 ;
    END
  END rw0_wd_in[10]
  PIN rw1_wd_in[11]
    DIRECTION INPUT ;
    USE SIGNAL ;
    SHAPE ABUTMENT ;
    PORT
      LAYER M3 ;
      RECT 7.839 0.000 7.857 0.036 ;
    END
  END rw1_wd_in[11]
  PIN rw0_wd_in[11]
    DIRECTION INPUT ;
    USE SIGNAL ;
    SHAPE ABUTMENT ;
    PORT
      LAYER M3 ;
      RECT 8.127 0.000 8.145 0.036 ;
    END
  END rw0_wd_in[11]
  PIN rw1_wd_in[12]
    DIRECTION INPUT ;
    USE SIGNAL ;
    SHAPE ABUTMENT ;
    PORT
      LAYER M3 ;
      RECT 8.379 0.000 8.397 0.036 ;
    END
  END rw1_wd_in[12]
  PIN rw0_wd_in[12]
    DIRECTION INPUT ;
    USE SIGNAL ;
    SHAPE ABUTMENT ;
    PORT
      LAYER M3 ;
      RECT 8.667 0.000 8.685 0.036 ;
    END
  END rw0_wd_in[12]
  PIN rw1_wd_in[13]
    DIRECTION INPUT ;
    USE SIGNAL ;
    SHAPE ABUTMENT ;
    PORT
      LAYER M3 ;
      RECT 8.919 0.000 8.937 0.036 ;
    END
  END rw1_wd_in[13]
  PIN rw0_wd_in[13]
    DIRECTION INPUT ;
    USE SIGNAL ;
    SHAPE ABUTMENT ;
    PORT
      LAYER M3 ;
      RECT 9.207 0.000 9.225 0.036 ;
    END
  END rw0_wd_in[13]
  PIN rw1_wd_in[14]
    DIRECTION INPUT ;
    USE SIGNAL ;
    SHAPE ABUTMENT ;
    PORT
      LAYER M3 ;
      RECT 9.459 0.000 9.477 0.036 ;
    END
  END rw1_wd_in[14]
  PIN rw0_wd_in[14]
    DIRECTION INPUT ;
    USE SIGNAL ;
    SHAPE ABUTMENT ;
    PORT
      LAYER M3 ;
      RECT 9.747 0.000 9.765 0.036 ;
    END
  END rw0_wd_in[14]
  PIN rw1_wd_in[15]
    DIRECTION INPUT ;
    USE SIGNAL ;
    SHAPE ABUTMENT ;
    PORT
      LAYER M3 ;
      RECT 9.999 0.000 10.017 0.036 ;
    END
  END rw1_wd_in[15]
  PIN rw0_wd_in[15]
    DIRECTION INPUT ;
    USE SIGNAL ;
    SHAPE ABUTMENT ;
    PORT
      LAYER M3 ;
      RECT 10.287 0.000 10.305 0.036 ;
    END
  END rw0_wd_in[15]
  PIN rw1_wd_in[16]
    DIRECTION INPUT ;
    USE SIGNAL ;
    SHAPE ABUTMENT ;
    PORT
      LAYER M3 ;
      RECT 10.539 0.000 10.557 0.036 ;
    END
  END rw1_wd_in[16]
  PIN rw0_wd_in[16]
    DIRECTION INPUT ;
    USE SIGNAL ;
    SHAPE ABUTMENT ;
    PORT
      LAYER M3 ;
      RECT 10.827 0.000 10.845 0.036 ;
    END
  END rw0_wd_in[16]
  PIN rw1_wd_in[17]
    DIRECTION INPUT ;
    USE SIGNAL ;
    SHAPE ABUTMENT ;
    PORT
      LAYER M3 ;
      RECT 11.079 0.000 11.097 0.036 ;
    END
  END rw1_wd_in[17]
  PIN rw0_wd_in[17]
    DIRECTION INPUT ;
    USE SIGNAL ;
    SHAPE ABUTMENT ;
    PORT
      LAYER M3 ;
      RECT 11.367 0.000 11.385 0.036 ;
    END
  END rw0_wd_in[17]
  PIN rw1_wd_in[18]
    DIRECTION INPUT ;
    USE SIGNAL ;
    SHAPE ABUTMENT ;
    PORT
      LAYER M3 ;
      RECT 11.619 0.000 11.637 0.036 ;
    END
  END rw1_wd_in[18]
  PIN rw0_wd_in[18]
    DIRECTION INPUT ;
    USE SIGNAL ;
    SHAPE ABUTMENT ;
    PORT
      LAYER M3 ;
      RECT 11.871 0.000 11.889 0.036 ;
    END
  END rw0_wd_in[18]
  PIN rw1_wd_in[19]
    DIRECTION INPUT ;
    USE SIGNAL ;
    SHAPE ABUTMENT ;
    PORT
      LAYER M3 ;
      RECT 12.159 0.000 12.177 0.036 ;
    END
  END rw1_wd_in[19]
  PIN rw0_wd_in[19]
    DIRECTION INPUT ;
    USE SIGNAL ;
    SHAPE ABUTMENT ;
    PORT
      LAYER M3 ;
      RECT 12.411 0.000 12.429 0.036 ;
    END
  END rw0_wd_in[19]
  PIN rw1_wd_in[20]
    DIRECTION INPUT ;
    USE SIGNAL ;
    SHAPE ABUTMENT ;
    PORT
      LAYER M3 ;
      RECT 12.699 0.000 12.717 0.036 ;
    END
  END rw1_wd_in[20]
  PIN rw0_wd_in[20]
    DIRECTION INPUT ;
    USE SIGNAL ;
    SHAPE ABUTMENT ;
    PORT
      LAYER M3 ;
      RECT 12.951 0.000 12.969 0.036 ;
    END
  END rw0_wd_in[20]
  PIN rw1_wd_in[21]
    DIRECTION INPUT ;
    USE SIGNAL ;
    SHAPE ABUTMENT ;
    PORT
      LAYER M3 ;
      RECT 13.239 0.000 13.257 0.036 ;
    END
  END rw1_wd_in[21]
  PIN rw0_wd_in[21]
    DIRECTION INPUT ;
    USE SIGNAL ;
    SHAPE ABUTMENT ;
    PORT
      LAYER M3 ;
      RECT 13.491 0.000 13.509 0.036 ;
    END
  END rw0_wd_in[21]
  PIN rw1_wd_in[22]
    DIRECTION INPUT ;
    USE SIGNAL ;
    SHAPE ABUTMENT ;
    PORT
      LAYER M3 ;
      RECT 13.779 0.000 13.797 0.036 ;
    END
  END rw1_wd_in[22]
  PIN rw0_wd_in[22]
    DIRECTION INPUT ;
    USE SIGNAL ;
    SHAPE ABUTMENT ;
    PORT
      LAYER M3 ;
      RECT 14.031 0.000 14.049 0.036 ;
    END
  END rw0_wd_in[22]
  PIN rw1_wd_in[23]
    DIRECTION INPUT ;
    USE SIGNAL ;
    SHAPE ABUTMENT ;
    PORT
      LAYER M3 ;
      RECT 14.319 0.000 14.337 0.036 ;
    END
  END rw1_wd_in[23]
  PIN rw0_wd_in[23]
    DIRECTION INPUT ;
    USE SIGNAL ;
    SHAPE ABUTMENT ;
    PORT
      LAYER M3 ;
      RECT 14.571 0.000 14.589 0.036 ;
    END
  END rw0_wd_in[23]
  PIN rw1_wd_in[24]
    DIRECTION INPUT ;
    USE SIGNAL ;
    SHAPE ABUTMENT ;
    PORT
      LAYER M3 ;
      RECT 14.859 0.000 14.877 0.036 ;
    END
  END rw1_wd_in[24]
  PIN rw0_wd_in[24]
    DIRECTION INPUT ;
    USE SIGNAL ;
    SHAPE ABUTMENT ;
    PORT
      LAYER M3 ;
      RECT 15.111 0.000 15.129 0.036 ;
    END
  END rw0_wd_in[24]
  PIN rw1_wd_in[25]
    DIRECTION INPUT ;
    USE SIGNAL ;
    SHAPE ABUTMENT ;
    PORT
      LAYER M3 ;
      RECT 15.399 0.000 15.417 0.036 ;
    END
  END rw1_wd_in[25]
  PIN rw0_wd_in[25]
    DIRECTION INPUT ;
    USE SIGNAL ;
    SHAPE ABUTMENT ;
    PORT
      LAYER M3 ;
      RECT 15.651 0.000 15.669 0.036 ;
    END
  END rw0_wd_in[25]
  PIN rw1_wd_in[26]
    DIRECTION INPUT ;
    USE SIGNAL ;
    SHAPE ABUTMENT ;
    PORT
      LAYER M3 ;
      RECT 15.939 0.000 15.957 0.036 ;
    END
  END rw1_wd_in[26]
  PIN rw0_wd_in[26]
    DIRECTION INPUT ;
    USE SIGNAL ;
    SHAPE ABUTMENT ;
    PORT
      LAYER M3 ;
      RECT 16.191 0.000 16.209 0.036 ;
    END
  END rw0_wd_in[26]
  PIN rw1_wd_in[27]
    DIRECTION INPUT ;
    USE SIGNAL ;
    SHAPE ABUTMENT ;
    PORT
      LAYER M3 ;
      RECT 16.479 0.000 16.497 0.036 ;
    END
  END rw1_wd_in[27]
  PIN rw0_wd_in[27]
    DIRECTION INPUT ;
    USE SIGNAL ;
    SHAPE ABUTMENT ;
    PORT
      LAYER M3 ;
      RECT 16.731 0.000 16.749 0.036 ;
    END
  END rw0_wd_in[27]
  PIN rw1_wd_in[28]
    DIRECTION INPUT ;
    USE SIGNAL ;
    SHAPE ABUTMENT ;
    PORT
      LAYER M3 ;
      RECT 16.983 0.000 17.001 0.036 ;
    END
  END rw1_wd_in[28]
  PIN rw0_wd_in[28]
    DIRECTION INPUT ;
    USE SIGNAL ;
    SHAPE ABUTMENT ;
    PORT
      LAYER M3 ;
      RECT 17.271 0.000 17.289 0.036 ;
    END
  END rw0_wd_in[28]
  PIN rw1_wd_in[29]
    DIRECTION INPUT ;
    USE SIGNAL ;
    SHAPE ABUTMENT ;
    PORT
      LAYER M3 ;
      RECT 17.523 0.000 17.541 0.036 ;
    END
  END rw1_wd_in[29]
  PIN rw0_wd_in[29]
    DIRECTION INPUT ;
    USE SIGNAL ;
    SHAPE ABUTMENT ;
    PORT
      LAYER M3 ;
      RECT 17.811 0.000 17.829 0.036 ;
    END
  END rw0_wd_in[29]
  PIN rw1_wd_in[30]
    DIRECTION INPUT ;
    USE SIGNAL ;
    SHAPE ABUTMENT ;
    PORT
      LAYER M3 ;
      RECT 18.063 0.000 18.081 0.036 ;
    END
  END rw1_wd_in[30]
  PIN rw0_wd_in[30]
    DIRECTION INPUT ;
    USE SIGNAL ;
    SHAPE ABUTMENT ;
    PORT
      LAYER M3 ;
      RECT 18.351 0.000 18.369 0.036 ;
    END
  END rw0_wd_in[30]
  PIN rw1_wd_in[31]
    DIRECTION INPUT ;
    USE SIGNAL ;
    SHAPE ABUTMENT ;
    PORT
      LAYER M3 ;
      RECT 18.603 0.000 18.621 0.036 ;
    END
  END rw1_wd_in[31]
  PIN rw0_wd_in[31]
    DIRECTION INPUT ;
    USE SIGNAL ;
    SHAPE ABUTMENT ;
    PORT
      LAYER M3 ;
      RECT 18.891 0.000 18.909 0.036 ;
    END
  END rw0_wd_in[31]
  PIN rw1_wd_in[32]
    DIRECTION INPUT ;
    USE SIGNAL ;
    SHAPE ABUTMENT ;
    PORT
      LAYER M3 ;
      RECT 19.143 0.000 19.161 0.036 ;
    END
  END rw1_wd_in[32]
  PIN rw0_wd_in[32]
    DIRECTION INPUT ;
    USE SIGNAL ;
    SHAPE ABUTMENT ;
    PORT
      LAYER M3 ;
      RECT 19.431 0.000 19.449 0.036 ;
    END
  END rw0_wd_in[32]
  PIN rw1_wd_in[33]
    DIRECTION INPUT ;
    USE SIGNAL ;
    SHAPE ABUTMENT ;
    PORT
      LAYER M3 ;
      RECT 19.683 0.000 19.701 0.036 ;
    END
  END rw1_wd_in[33]
  PIN rw0_wd_in[33]
    DIRECTION INPUT ;
    USE SIGNAL ;
    SHAPE ABUTMENT ;
    PORT
      LAYER M3 ;
      RECT 19.971 0.000 19.989 0.036 ;
    END
  END rw0_wd_in[33]
  PIN rw1_wd_in[34]
    DIRECTION INPUT ;
    USE SIGNAL ;
    SHAPE ABUTMENT ;
    PORT
      LAYER M3 ;
      RECT 20.223 0.000 20.241 0.036 ;
    END
  END rw1_wd_in[34]
  PIN rw0_wd_in[34]
    DIRECTION INPUT ;
    USE SIGNAL ;
    SHAPE ABUTMENT ;
    PORT
      LAYER M3 ;
      RECT 20.511 0.000 20.529 0.036 ;
    END
  END rw0_wd_in[34]
  PIN rw1_wd_in[35]
    DIRECTION INPUT ;
    USE SIGNAL ;
    SHAPE ABUTMENT ;
    PORT
      LAYER M3 ;
      RECT 20.763 0.000 20.781 0.036 ;
    END
  END rw1_wd_in[35]
  PIN rw0_wd_in[35]
    DIRECTION INPUT ;
    USE SIGNAL ;
    SHAPE ABUTMENT ;
    PORT
      LAYER M3 ;
      RECT 21.051 0.000 21.069 0.036 ;
    END
  END rw0_wd_in[35]
  PIN rw1_wd_in[36]
    DIRECTION INPUT ;
    USE SIGNAL ;
    SHAPE ABUTMENT ;
    PORT
      LAYER M3 ;
      RECT 21.303 0.000 21.321 0.036 ;
    END
  END rw1_wd_in[36]
  PIN rw0_wd_in[36]
    DIRECTION INPUT ;
    USE SIGNAL ;
    SHAPE ABUTMENT ;
    PORT
      LAYER M3 ;
      RECT 21.555 0.000 21.573 0.036 ;
    END
  END rw0_wd_in[36]
  PIN rw1_wd_in[37]
    DIRECTION INPUT ;
    USE SIGNAL ;
    SHAPE ABUTMENT ;
    PORT
      LAYER M3 ;
      RECT 21.843 0.000 21.861 0.036 ;
    END
  END rw1_wd_in[37]
  PIN rw0_wd_in[37]
    DIRECTION INPUT ;
    USE SIGNAL ;
    SHAPE ABUTMENT ;
    PORT
      LAYER M3 ;
      RECT 22.095 0.000 22.113 0.036 ;
    END
  END rw0_wd_in[37]
  PIN rw1_wd_in[38]
    DIRECTION INPUT ;
    USE SIGNAL ;
    SHAPE ABUTMENT ;
    PORT
      LAYER M3 ;
      RECT 22.383 0.000 22.401 0.036 ;
    END
  END rw1_wd_in[38]
  PIN rw0_wd_in[38]
    DIRECTION INPUT ;
    USE SIGNAL ;
    SHAPE ABUTMENT ;
    PORT
      LAYER M3 ;
      RECT 22.635 0.000 22.653 0.036 ;
    END
  END rw0_wd_in[38]
  PIN rw1_wd_in[39]
    DIRECTION INPUT ;
    USE SIGNAL ;
    SHAPE ABUTMENT ;
    PORT
      LAYER M3 ;
      RECT 22.923 0.000 22.941 0.036 ;
    END
  END rw1_wd_in[39]
  PIN rw0_wd_in[39]
    DIRECTION INPUT ;
    USE SIGNAL ;
    SHAPE ABUTMENT ;
    PORT
      LAYER M3 ;
      RECT 23.175 0.000 23.193 0.036 ;
    END
  END rw0_wd_in[39]
  PIN rw1_wd_in[40]
    DIRECTION INPUT ;
    USE SIGNAL ;
    SHAPE ABUTMENT ;
    PORT
      LAYER M3 ;
      RECT 23.463 0.000 23.481 0.036 ;
    END
  END rw1_wd_in[40]
  PIN rw0_wd_in[40]
    DIRECTION INPUT ;
    USE SIGNAL ;
    SHAPE ABUTMENT ;
    PORT
      LAYER M3 ;
      RECT 23.715 0.000 23.733 0.036 ;
    END
  END rw0_wd_in[40]
  PIN rw1_wd_in[41]
    DIRECTION INPUT ;
    USE SIGNAL ;
    SHAPE ABUTMENT ;
    PORT
      LAYER M3 ;
      RECT 24.003 0.000 24.021 0.036 ;
    END
  END rw1_wd_in[41]
  PIN rw0_wd_in[41]
    DIRECTION INPUT ;
    USE SIGNAL ;
    SHAPE ABUTMENT ;
    PORT
      LAYER M3 ;
      RECT 24.255 0.000 24.273 0.036 ;
    END
  END rw0_wd_in[41]
  PIN rw1_wd_in[42]
    DIRECTION INPUT ;
    USE SIGNAL ;
    SHAPE ABUTMENT ;
    PORT
      LAYER M3 ;
      RECT 24.543 0.000 24.561 0.036 ;
    END
  END rw1_wd_in[42]
  PIN rw0_wd_in[42]
    DIRECTION INPUT ;
    USE SIGNAL ;
    SHAPE ABUTMENT ;
    PORT
      LAYER M3 ;
      RECT 24.795 0.000 24.813 0.036 ;
    END
  END rw0_wd_in[42]
  PIN rw1_wd_in[43]
    DIRECTION INPUT ;
    USE SIGNAL ;
    SHAPE ABUTMENT ;
    PORT
      LAYER M3 ;
      RECT 25.083 0.000 25.101 0.036 ;
    END
  END rw1_wd_in[43]
  PIN rw0_wd_in[43]
    DIRECTION INPUT ;
    USE SIGNAL ;
    SHAPE ABUTMENT ;
    PORT
      LAYER M3 ;
      RECT 25.335 0.000 25.353 0.036 ;
    END
  END rw0_wd_in[43]
  PIN rw1_wd_in[44]
    DIRECTION INPUT ;
    USE SIGNAL ;
    SHAPE ABUTMENT ;
    PORT
      LAYER M3 ;
      RECT 25.623 0.000 25.641 0.036 ;
    END
  END rw1_wd_in[44]
  PIN rw0_wd_in[44]
    DIRECTION INPUT ;
    USE SIGNAL ;
    SHAPE ABUTMENT ;
    PORT
      LAYER M3 ;
      RECT 25.875 0.000 25.893 0.036 ;
    END
  END rw0_wd_in[44]
  PIN rw1_wd_in[45]
    DIRECTION INPUT ;
    USE SIGNAL ;
    SHAPE ABUTMENT ;
    PORT
      LAYER M3 ;
      RECT 26.163 0.000 26.181 0.036 ;
    END
  END rw1_wd_in[45]
  PIN rw0_wd_in[45]
    DIRECTION INPUT ;
    USE SIGNAL ;
    SHAPE ABUTMENT ;
    PORT
      LAYER M3 ;
      RECT 26.415 0.000 26.433 0.036 ;
    END
  END rw0_wd_in[45]
  PIN rw1_wd_in[46]
    DIRECTION INPUT ;
    USE SIGNAL ;
    SHAPE ABUTMENT ;
    PORT
      LAYER M3 ;
      RECT 26.667 0.000 26.685 0.036 ;
    END
  END rw1_wd_in[46]
  PIN rw0_wd_in[46]
    DIRECTION INPUT ;
    USE SIGNAL ;
    SHAPE ABUTMENT ;
    PORT
      LAYER M3 ;
      RECT 26.955 0.000 26.973 0.036 ;
    END
  END rw0_wd_in[46]
  PIN rw1_wd_in[47]
    DIRECTION INPUT ;
    USE SIGNAL ;
    SHAPE ABUTMENT ;
    PORT
      LAYER M3 ;
      RECT 27.207 0.000 27.225 0.036 ;
    END
  END rw1_wd_in[47]
  PIN rw0_wd_in[47]
    DIRECTION INPUT ;
    USE SIGNAL ;
    SHAPE ABUTMENT ;
    PORT
      LAYER M3 ;
      RECT 27.495 0.000 27.513 0.036 ;
    END
  END rw0_wd_in[47]
  PIN rw1_wd_in[48]
    DIRECTION INPUT ;
    USE SIGNAL ;
    SHAPE ABUTMENT ;
    PORT
      LAYER M3 ;
      RECT 27.747 0.000 27.765 0.036 ;
    END
  END rw1_wd_in[48]
  PIN rw0_wd_in[48]
    DIRECTION INPUT ;
    USE SIGNAL ;
    SHAPE ABUTMENT ;
    PORT
      LAYER M3 ;
      RECT 28.035 0.000 28.053 0.036 ;
    END
  END rw0_wd_in[48]
  PIN rw1_wd_in[49]
    DIRECTION INPUT ;
    USE SIGNAL ;
    SHAPE ABUTMENT ;
    PORT
      LAYER M3 ;
      RECT 28.287 0.000 28.305 0.036 ;
    END
  END rw1_wd_in[49]
  PIN rw0_wd_in[49]
    DIRECTION INPUT ;
    USE SIGNAL ;
    SHAPE ABUTMENT ;
    PORT
      LAYER M3 ;
      RECT 28.575 0.000 28.593 0.036 ;
    END
  END rw0_wd_in[49]
  PIN rw1_wd_in[50]
    DIRECTION INPUT ;
    USE SIGNAL ;
    SHAPE ABUTMENT ;
    PORT
      LAYER M3 ;
      RECT 28.827 0.000 28.845 0.036 ;
    END
  END rw1_wd_in[50]
  PIN rw0_wd_in[50]
    DIRECTION INPUT ;
    USE SIGNAL ;
    SHAPE ABUTMENT ;
    PORT
      LAYER M3 ;
      RECT 29.115 0.000 29.133 0.036 ;
    END
  END rw0_wd_in[50]
  PIN rw1_wd_in[51]
    DIRECTION INPUT ;
    USE SIGNAL ;
    SHAPE ABUTMENT ;
    PORT
      LAYER M3 ;
      RECT 29.367 0.000 29.385 0.036 ;
    END
  END rw1_wd_in[51]
  PIN rw0_wd_in[51]
    DIRECTION INPUT ;
    USE SIGNAL ;
    SHAPE ABUTMENT ;
    PORT
      LAYER M3 ;
      RECT 29.655 0.000 29.673 0.036 ;
    END
  END rw0_wd_in[51]
  PIN rw1_wd_in[52]
    DIRECTION INPUT ;
    USE SIGNAL ;
    SHAPE ABUTMENT ;
    PORT
      LAYER M3 ;
      RECT 29.907 0.000 29.925 0.036 ;
    END
  END rw1_wd_in[52]
  PIN rw0_wd_in[52]
    DIRECTION INPUT ;
    USE SIGNAL ;
    SHAPE ABUTMENT ;
    PORT
      LAYER M3 ;
      RECT 30.195 0.000 30.213 0.036 ;
    END
  END rw0_wd_in[52]
  PIN rw1_wd_in[53]
    DIRECTION INPUT ;
    USE SIGNAL ;
    SHAPE ABUTMENT ;
    PORT
      LAYER M3 ;
      RECT 30.447 0.000 30.465 0.036 ;
    END
  END rw1_wd_in[53]
  PIN rw0_wd_in[53]
    DIRECTION INPUT ;
    USE SIGNAL ;
    SHAPE ABUTMENT ;
    PORT
      LAYER M3 ;
      RECT 30.735 0.000 30.753 0.036 ;
    END
  END rw0_wd_in[53]
  PIN rw1_wd_in[54]
    DIRECTION INPUT ;
    USE SIGNAL ;
    SHAPE ABUTMENT ;
    PORT
      LAYER M3 ;
      RECT 30.987 0.000 31.005 0.036 ;
    END
  END rw1_wd_in[54]
  PIN rw0_wd_in[54]
    DIRECTION INPUT ;
    USE SIGNAL ;
    SHAPE ABUTMENT ;
    PORT
      LAYER M3 ;
      RECT 31.239 0.000 31.257 0.036 ;
    END
  END rw0_wd_in[54]
  PIN rw1_wd_in[55]
    DIRECTION INPUT ;
    USE SIGNAL ;
    SHAPE ABUTMENT ;
    PORT
      LAYER M3 ;
      RECT 31.527 0.000 31.545 0.036 ;
    END
  END rw1_wd_in[55]
  PIN rw0_wd_in[55]
    DIRECTION INPUT ;
    USE SIGNAL ;
    SHAPE ABUTMENT ;
    PORT
      LAYER M3 ;
      RECT 31.779 0.000 31.797 0.036 ;
    END
  END rw0_wd_in[55]
  PIN rw1_wd_in[56]
    DIRECTION INPUT ;
    USE SIGNAL ;
    SHAPE ABUTMENT ;
    PORT
      LAYER M3 ;
      RECT 32.067 0.000 32.085 0.036 ;
    END
  END rw1_wd_in[56]
  PIN rw0_wd_in[56]
    DIRECTION INPUT ;
    USE SIGNAL ;
    SHAPE ABUTMENT ;
    PORT
      LAYER M3 ;
      RECT 32.319 0.000 32.337 0.036 ;
    END
  END rw0_wd_in[56]
  PIN rw1_wd_in[57]
    DIRECTION INPUT ;
    USE SIGNAL ;
    SHAPE ABUTMENT ;
    PORT
      LAYER M3 ;
      RECT 32.607 0.000 32.625 0.036 ;
    END
  END rw1_wd_in[57]
  PIN rw0_wd_in[57]
    DIRECTION INPUT ;
    USE SIGNAL ;
    SHAPE ABUTMENT ;
    PORT
      LAYER M3 ;
      RECT 32.859 0.000 32.877 0.036 ;
    END
  END rw0_wd_in[57]
  PIN rw1_wd_in[58]
    DIRECTION INPUT ;
    USE SIGNAL ;
    SHAPE ABUTMENT ;
    PORT
      LAYER M3 ;
      RECT 33.147 0.000 33.165 0.036 ;
    END
  END rw1_wd_in[58]
  PIN rw0_wd_in[58]
    DIRECTION INPUT ;
    USE SIGNAL ;
    SHAPE ABUTMENT ;
    PORT
      LAYER M3 ;
      RECT 33.399 0.000 33.417 0.036 ;
    END
  END rw0_wd_in[58]
  PIN rw1_wd_in[59]
    DIRECTION INPUT ;
    USE SIGNAL ;
    SHAPE ABUTMENT ;
    PORT
      LAYER M3 ;
      RECT 33.687 0.000 33.705 0.036 ;
    END
  END rw1_wd_in[59]
  PIN rw0_wd_in[59]
    DIRECTION INPUT ;
    USE SIGNAL ;
    SHAPE ABUTMENT ;
    PORT
      LAYER M3 ;
      RECT 33.939 0.000 33.957 0.036 ;
    END
  END rw0_wd_in[59]
  PIN rw1_wd_in[60]
    DIRECTION INPUT ;
    USE SIGNAL ;
    SHAPE ABUTMENT ;
    PORT
      LAYER M3 ;
      RECT 34.227 0.000 34.245 0.036 ;
    END
  END rw1_wd_in[60]
  PIN rw0_wd_in[60]
    DIRECTION INPUT ;
    USE SIGNAL ;
    SHAPE ABUTMENT ;
    PORT
      LAYER M3 ;
      RECT 34.479 0.000 34.497 0.036 ;
    END
  END rw0_wd_in[60]
  PIN rw1_wd_in[61]
    DIRECTION INPUT ;
    USE SIGNAL ;
    SHAPE ABUTMENT ;
    PORT
      LAYER M3 ;
      RECT 34.767 0.000 34.785 0.036 ;
    END
  END rw1_wd_in[61]
  PIN rw0_wd_in[61]
    DIRECTION INPUT ;
    USE SIGNAL ;
    SHAPE ABUTMENT ;
    PORT
      LAYER M3 ;
      RECT 35.019 0.000 35.037 0.036 ;
    END
  END rw0_wd_in[61]
  PIN rw1_wd_in[62]
    DIRECTION INPUT ;
    USE SIGNAL ;
    SHAPE ABUTMENT ;
    PORT
      LAYER M3 ;
      RECT 35.307 0.000 35.325 0.036 ;
    END
  END rw1_wd_in[62]
  PIN rw0_wd_in[62]
    DIRECTION INPUT ;
    USE SIGNAL ;
    SHAPE ABUTMENT ;
    PORT
      LAYER M3 ;
      RECT 35.559 0.000 35.577 0.036 ;
    END
  END rw0_wd_in[62]
  PIN rw1_wd_in[63]
    DIRECTION INPUT ;
    USE SIGNAL ;
    SHAPE ABUTMENT ;
    PORT
      LAYER M3 ;
      RECT 35.847 0.000 35.865 0.036 ;
    END
  END rw1_wd_in[63]
  PIN rw0_wd_in[63]
    DIRECTION INPUT ;
    USE SIGNAL ;
    SHAPE ABUTMENT ;
    PORT
      LAYER M3 ;
      RECT 36.099 0.000 36.117 0.036 ;
    END
  END rw0_wd_in[63]
  PIN VSS
    DIRECTION INOUT ;
    USE GROUND ;
    PORT
      LAYER M4 ;
      RECT 0.096 0.816 37.920 0.912 ;
      RECT 0.096 1.584 37.920 1.680 ;
      RECT 0.096 2.352 37.920 2.448 ;
      RECT 0.096 3.120 37.920 3.216 ;
      RECT 0.096 3.888 37.920 3.984 ;
      RECT 0.096 4.656 37.920 4.752 ;
      RECT 0.096 5.424 37.920 5.520 ;
      RECT 0.096 6.192 37.920 6.288 ;
      RECT 0.096 6.960 37.920 7.056 ;
      RECT 0.096 7.728 37.920 7.824 ;
      RECT 0.096 8.496 37.920 8.592 ;
      RECT 0.096 9.264 37.920 9.360 ;
      RECT 0.096 10.032 37.920 10.128 ;
      RECT 0.096 10.800 37.920 10.896 ;
      RECT 0.096 11.568 37.920 11.664 ;
      RECT 0.096 12.336 37.920 12.432 ;
      RECT 0.096 13.104 37.920 13.200 ;
      RECT 0.096 13.872 37.920 13.968 ;
      RECT 0.096 14.640 37.920 14.736 ;
      RECT 0.096 15.408 37.920 15.504 ;
      RECT 0.096 16.176 37.920 16.272 ;
      RECT 0.096 16.944 37.920 17.040 ;
      RECT 0.096 17.712 37.920 17.808 ;
      RECT 0.096 18.480 37.920 18.576 ;
      RECT 0.096 19.248 37.920 19.344 ;
      RECT 0.096 20.016 37.920 20.112 ;
      RECT 0.096 20.784 37.920 20.880 ;
      RECT 0.096 21.552 37.920 21.648 ;
      RECT 0.096 22.320 37.920 22.416 ;
      RECT 0.096 23.088 37.920 23.184 ;
      RECT 0.096 23.856 37.920 23.952 ;
      RECT 0.096 24.624 37.920 24.720 ;
      RECT 0.096 25.392 37.920 25.488 ;
      RECT 0.096 26.160 37.920 26.256 ;
      RECT 0.096 26.928 37.920 27.024 ;
      RECT 0.096 27.696 37.920 27.792 ;
      RECT 0.096 28.464 37.920 28.560 ;
      RECT 0.096 29.232 37.920 29.328 ;
      RECT 0.096 30.000 37.920 30.096 ;
      RECT 0.096 30.768 37.920 30.864 ;
      RECT 0.096 31.536 37.920 31.632 ;
      RECT 0.096 32.304 37.920 32.400 ;
      RECT 0.096 33.072 37.920 33.168 ;
      RECT 0.096 33.840 37.920 33.936 ;
    END
  END VSS
  PIN VDD
    DIRECTION INOUT ;
    USE POWER ;
    PORT
      LAYER M4 ;
      RECT 0.096 0.432 37.920 0.528 ;
      RECT 0.096 1.200 37.920 1.296 ;
      RECT 0.096 1.968 37.920 2.064 ;
      RECT 0.096 2.736 37.920 2.832 ;
      RECT 0.096 3.504 37.920 3.600 ;
      RECT 0.096 4.272 37.920 4.368 ;
      RECT 0.096 5.040 37.920 5.136 ;
      RECT 0.096 5.808 37.920 5.904 ;
      RECT 0.096 6.576 37.920 6.672 ;
      RECT 0.096 7.344 37.920 7.440 ;
      RECT 0.096 8.112 37.920 8.208 ;
      RECT 0.096 8.880 37.920 8.976 ;
      RECT 0.096 9.648 37.920 9.744 ;
      RECT 0.096 10.416 37.920 10.512 ;
      RECT 0.096 11.184 37.920 11.280 ;
      RECT 0.096 11.952 37.920 12.048 ;
      RECT 0.096 12.720 37.920 12.816 ;
      RECT 0.096 13.488 37.920 13.584 ;
      RECT 0.096 14.256 37.920 14.352 ;
      RECT 0.096 15.024 37.920 15.120 ;
      RECT 0.096 15.792 37.920 15.888 ;
      RECT 0.096 16.560 37.920 16.656 ;
      RECT 0.096 17.328 37.920 17.424 ;
      RECT 0.096 18.096 37.920 18.192 ;
      RECT 0.096 18.864 37.920 18.960 ;
      RECT 0.096 19.632 37.920 19.728 ;
      RECT 0.096 20.400 37.920 20.496 ;
      RECT 0.096 21.168 37.920 21.264 ;
      RECT 0.096 21.936 37.920 22.032 ;
      RECT 0.096 22.704 37.920 22.800 ;
      RECT 0.096 23.472 37.920 23.568 ;
      RECT 0.096 24.240 37.920 24.336 ;
      RECT 0.096 25.008 37.920 25.104 ;
      RECT 0.096 25.776 37.920 25.872 ;
      RECT 0.096 26.544 37.920 26.640 ;
      RECT 0.096 27.312 37.920 27.408 ;
      RECT 0.096 28.080 37.920 28.176 ;
      RECT 0.096 28.848 37.920 28.944 ;
      RECT 0.096 29.616 37.920 29.712 ;
      RECT 0.096 30.384 37.920 30.480 ;
      RECT 0.096 31.152 37.920 31.248 ;
      RECT 0.096 31.920 37.920 32.016 ;
      RECT 0.096 32.688 37.920 32.784 ;
      RECT 0.096 33.456 37.920 33.552 ;
    END
  END VDD
  OBS
    LAYER M1 ;
    RECT 0 0 38.016 34.032 ;
    LAYER M2 ;
    RECT 0 0 38.016 34.032 ;
    LAYER M3 ;
    RECT 0 0 38.016 34.032 ;
    LAYER M4 ;
    RECT 0 0 38.016 34.032 ;
  END
END fakeram_w64_l256

END LIBRARY
